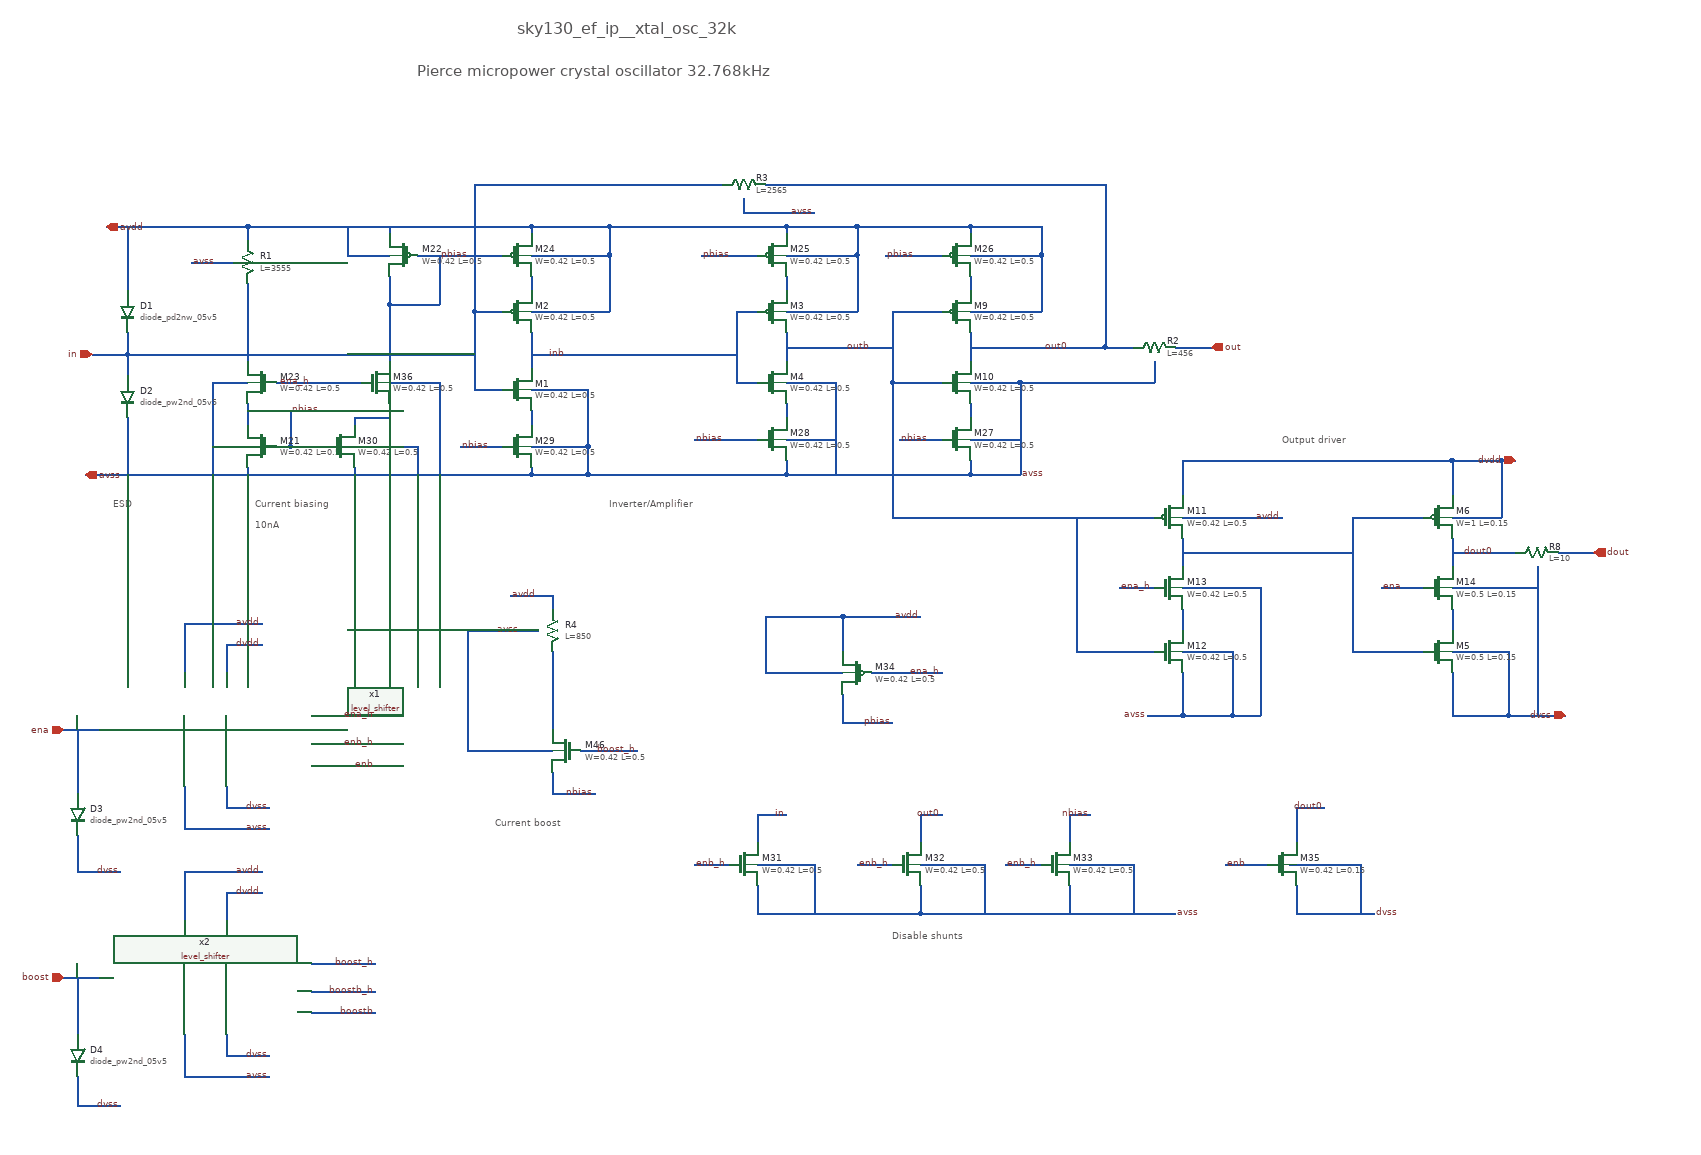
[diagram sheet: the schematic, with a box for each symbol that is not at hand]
v {xschem version=3.4.5 file_version=1.2
}
G {}
K {}
V {}
S {}
E {}
T {Inverter/Amplifier} 0 210 0 0 0.4 0.4 {}
T {Output driver} 950 120 0 0 0.4 0.4 {}
T {Disable shunts} 400 820 0 0 0.4 0.4 {}
T {Pierce micropower crystal oscillator 32.768kHz} -270 -400 0 0 0.65 0.65 {}
T {Current biasing} -500 210 0 0 0.4 0.4 {}
T {ESD} -700 210 0 0 0.4 0.4 {}
T {10nA} -500 240 0 0 0.4 0.4 {}
T {Current boost} -160 660 0 0 0.4 0.4 {}
T {sky130_ef_ip__xtal_osc_32k} -130 -460 0 0 0.7 0.7 {}
N -110 -20 -110 30 {
lab=inb}
N -190 -50 -150 -50 {
lab=in}
N -190 -50 -190 60 {
lab=in}
N -190 60 -150 60 {
lab=in}
N 250 -170 320 -170 {
lab=avdd}
N 250 180 310 180 {
lab=avss}
N -110 180 -30 180 {
lab=avss}
N -30 60 -30 140 {
lab=avss}
N -110 60 -30 60 {
lab=avss}
N -110 -50 0 -50 {
lab=avdd}
N 0 -130 0 -50 {
lab=avdd}
N -110 -170 0 -170 {
lab=avdd}
N 250 -20 250 20 {
lab=outb}
N 180 -50 180 50 {
lab=inb}
N 250 50 320 50 {
lab=avss}
N 310 180 340 180 {
lab=avss}
N 320 -170 350 -170 {
lab=avdd}
N 250 -50 350 -50 {
lab=avdd}
N 350 -130 350 -50 {
lab=avdd}
N 1190 160 1190 210 {
lab=dvdd}
N 1190 240 1260 240 {
lab=dvdd}
N 1260 160 1260 240 {
lab=dvdd}
N 1190 460 1190 520 {
lab=dvss}
N 1190 430 1270 430 {
lab=dvss}
N 1270 430 1270 520 {
lab=dvss}
N 220 -230 700 -230 {
lab=out0}
N 700 -230 700 -0 {
lab=out0}
N 720 0 740 -0 {
lab=out0}
N 800 -0 850 0 {
lab=out}
N 1190 160 1260 160 {
lab=dvdd}
N 1260 160 1280 160 {
lab=dvdd}
N 1190 520 1270 520 {
lab=dvss}
N 510 -170 580 -170 {
lab=avdd}
N 510 180 570 180 {
lab=avss}
N 510 -20 510 20 {
lab=out0}
N 420 -50 470 -50 {
lab=outb}
N 400 -50 400 50 {
lab=outb}
N 420 50 470 50 {
lab=outb}
N 510 50 580 50 {
lab=avss}
N 580 50 580 110 {
lab=avss}
N 580 110 580 140 {
lab=avss}
N 580 -170 610 -170 {
lab=avdd}
N 510 -50 610 -50 {
lab=avdd}
N 610 -130 610 -50 {
lab=avdd}
N 340 180 510 180 {
lab=avss}
N 570 180 580 180 {
lab=avss}
N 350 -170 510 -170 {
lab=avdd}
N 110 -170 250 -170 {
lab=avdd}
N 810 160 880 160 {
lab=dvdd}
N 810 160 810 210 {
lab=dvdd}
N 810 460 810 510 {
lab=avss}
N 810 510 810 520 {
lab=avss}
N 810 520 870 520 {
lab=avss}
N 720 430 770 430 {
lab=outb}
N 810 430 880 430 {
lab=avss}
N 880 430 880 490 {
lab=avss}
N 880 490 880 520 {
lab=avss}
N 880 160 910 160 {
lab=dvdd}
N 810 240 910 240 {
lab=avdd}
N 870 520 880 520 {
lab=avss}
N 910 160 1190 160 {
lab=dvdd}
N 910 240 950 240 {
lab=avdd}
N 400 50 400 240 {
lab=outb}
N 700 -0 720 0 {
lab=out0}
N 510 -0 700 0 {
lab=out0}
N 0 -170 0 -130 {
lab=avdd}
N 350 -170 350 -130 {
lab=avdd}
N 610 -170 610 -130 {
lab=avdd}
N -30 140 -30 180 {
lab=avss}
N 580 140 580 180 {
lab=avss}
N 320 50 320 180 {
lab=avss}
N 400 -50 420 -50 {
lab=outb}
N 400 50 420 50 {
lab=outb}
N 250 -0 400 -0 {
lab=outb}
N -680 -20 -680 10 {
lab=in}
N -680 10 -680 40 {
lab=in}
N -510 -170 -110 -170 {
lab=avdd}
N -680 -170 -680 -80 {
lab=avdd}
N -680 100 -680 180 {
lab=avss}
N 1270 520 1350 520 {
lab=dvss}
N 1190 290 1280 290 {
lab=dout0}
N 1340 290 1390 290 {
lab=dout}
N 1310 310 1310 520 {
lab=dvss}
N 810 340 920 340 {
lab=avss}
N 920 340 920 520 {
lab=avss}
N 1190 340 1310 340 {
lab=dvss}
N 810 270 810 310 {
lab=#net1}
N 810 370 810 400 {
lab=#net2}
N 1190 270 1190 310 {
lab=dout0}
N 1190 370 1190 400 {
lab=#net3}
N 660 240 660 430 {
lab=outb}
N 660 430 720 430 {
lab=outb}
N 810 290 1050 290 {
lab=#net1}
N 1050 240 1150 240 {
lab=#net1}
N 1050 240 1050 430 {
lab=#net1}
N 1050 430 1150 430 {
lab=#net1}
N 180 -50 210 -50 {
lab=inb}
N 180 50 210 50 {
lab=inb}
N 720 340 770 340 {
lab=ena_h}
N 190 -210 190 -190 {
lab=avss}
N 190 -190 290 -190 {
lab=avss}
N 770 20 770 50 {
lab=avss}
N 580 50 770 50 {
lab=avss}
N 0 -170 110 -170 {
lab=avdd}
N -190 -230 -190 -50 {
lab=in}
N -190 -230 160 -230 {
lab=in}
N 400 240 770 240 {
lab=outb}
N 510 80 510 100 {
lab=#net4}
N 510 130 580 130 {
lab=avss}
N 510 160 510 180 {
lab=avss}
N 510 -100 510 -80 {
lab=#net5}
N 510 -170 510 -160 {
lab=avdd}
N 510 -130 610 -130 {
lab=avdd}
N -110 -130 0 -130 {
lab=avdd}
N 250 -130 350 -130 {
lab=avdd}
N 250 -170 250 -160 {
lab=avdd}
N 250 -100 250 -80 {
lab=#net6}
N -110 -100 -110 -80 {
lab=#net7}
N -110 -170 -110 -160 {
lab=avdd}
N -110 90 -110 110 {
lab=#net8}
N -110 140 -30 140 {
lab=avss}
N -110 170 -110 180 {
lab=avss}
N 250 160 250 180 {
lab=avss}
N 250 80 250 100 {
lab=#net9}
N 250 130 320 130 {
lab=avss}
N -270 -130 -150 -130 {
lab=pbias}
N 130 -130 210 -130 {
lab=pbias}
N 390 -130 470 -130 {
lab=pbias}
N 410 130 470 130 {
lab=nbias}
N 120 130 210 130 {
lab=nbias}
N -110 10 180 10 {
lab=inb}
N -30 180 250 180 {
lab=avss}
N -510 170 -510 180 {
lab=avss}
N -730 10 -680 10 {
lab=in}
N -590 10 -190 10 {
lab=in}
N -470 140 -450 140 {
lab=nbias}
N -450 90 -450 140 {
lab=nbias}
N -510 90 -450 90 {
lab=nbias}
N -510 -170 -510 -150 {
lab=avdd}
N -510 80 -510 110 {
lab=nbias}
N -680 10 -590 10 {
lab=in}
N -590 -120 -530 -120 {
lab=avss}
N -510 -90 -510 20 {
lab=#net10}
N -450 140 -400 140 {
lab=nbias}
N -210 140 -150 140 {
lab=nbias}
N -360 170 -360 180 {
lab=avss}
N -360 140 -270 140 {
lab=avss}
N -270 140 -270 180 {
lab=avss}
N -310 -100 -310 -60 {
lab=pbias}
N -310 -60 -240 -60 {
lab=pbias}
N -240 -130 -240 -60 {
lab=pbias}
N -370 -130 -310 -130 {
lab=avdd}
N -370 -170 -370 -130 {
lab=avdd}
N -710 -170 -510 -170 {
lab=avdd}
N -740 180 -110 180 {
lab=avss}
N -560 50 -510 50 {
lab=avss}
N -560 50 -560 180 {
lab=avss}
N -560 140 -510 140 {
lab=avss}
N 210 760 210 800 {
lab=avss}
N 210 800 440 800 {
lab=avss}
N 440 760 440 800 {
lab=avss}
N 440 730 530 730 {
lab=avss}
N 530 730 530 800 {
lab=avss}
N 210 730 290 730 {
lab=avss}
N 290 730 290 800 {
lab=avss}
N 440 660 440 700 {
lab=out0}
N 440 660 470 660 {
lab=out0}
N 210 660 210 700 {
lab=in}
N 210 660 250 660 {
lab=in}
N 120 730 170 730 {
lab=enb_h}
N 350 730 400 730 {
lab=enb_h}
N 650 760 650 800 {
lab=avss}
N 650 730 740 730 {
lab=avss}
N 740 730 740 800 {
lab=avss}
N 650 660 650 700 {
lab=nbias}
N 650 660 680 660 {
lab=nbias}
N 560 730 610 730 {
lab=enb_h}
N 440 800 800 800 {
lab=avss}
N 330 380 330 430 {
lab=avdd}
N 330 380 440 380 {
lab=avdd}
N 220 460 330 460 {
lab=avdd}
N 220 380 220 460 {
lab=avdd}
N 220 380 330 380 {
lab=avdd}
N 370 460 470 460 {
lab=ena_h}
N 330 490 330 530 {
lab=pbias}
N 330 530 400 530 {
lab=pbias}
N 1090 340 1150 340 {
lab=ena}
N 870 730 930 730 {
lab=enb}
N 970 650 970 700 {
lab=dout0}
N 970 650 1010 650 {
lab=dout0}
N 970 760 970 800 {
lab=dvss}
N 970 800 1080 800 {
lab=dvss}
N 960 730 1060 730 {
lab=dvss}
N 1060 730 1060 800 {
lab=dvss}
N -360 100 -360 110 {
lab=#net11}
N -360 100 -310 100 {
lab=#net11}
N -310 90 -310 100 {
lab=#net11}
N -310 20 -310 30 {
lab=pbias}
N -310 80 -310 90 {
lab=#net11}
N -310 50 -240 50 {
lab=avss}
N -240 50 -240 180 {
lab=avss}
N -310 -60 -310 20 {
lab=pbias}
N -470 50 -350 50 {
lab=ena_h}
N -310 -170 -310 -160 {
lab=avdd}
N -80 630 -20 630 {
lab=nbias}
N -80 350 -80 370 {
lab=avdd}
N -80 430 -80 540 {
lab=#net12}
N -140 350 -80 350 {
lab=avdd}
N -200 570 -80 570 {
lab=avss}
N -200 400 -200 570 {
lab=avss}
N -200 400 -100 400 {
lab=avss}
N -80 600 -80 630 {
lab=nbias}
N -40 570 40 570 {
lab=boost_h}
N -770 540 -720 540 {
lab=ena}
N -770 890 -720 890 {
lab=boost}
N -420 520 -330 520 {
lab=ena_h}
N -420 560 -330 560 {
lab=enb_h}
N -420 870 -330 870 {
lab=boost_h}
N -420 910 -330 910 {
lab=boostb_h}
N -540 420 -540 460 {
lab=dvdd}
N -540 420 -490 420 {
lab=dvdd}
N -600 390 -600 460 {
lab=avdd}
N -600 390 -490 390 {
lab=avdd}
N -540 620 -540 650 {
lab=dvss}
N -540 650 -480 650 {
lab=dvss}
N -600 620 -600 680 {
lab=avss}
N -600 680 -480 680 {
lab=avss}
N -540 770 -540 810 {
lab=dvdd}
N -540 770 -490 770 {
lab=dvdd}
N -600 740 -600 810 {
lab=avdd}
N -600 740 -490 740 {
lab=avdd}
N -540 970 -540 1000 {
lab=dvss}
N -540 1000 -480 1000 {
lab=dvss}
N -600 970 -600 1030 {
lab=avss}
N -600 1030 -480 1030 {
lab=avss}
N -420 590 -330 590 {
lab=enb}
N -420 940 -330 940 {
lab=boostb}
N 880 520 920 520 {
lab=avss}
N 760 520 810 520 {
lab=avss}
N -750 1030 -750 1070 {
lab=dvss}
N -750 1070 -690 1070 {
lab=dvss}
N -750 690 -750 740 {
lab=dvss}
N -750 740 -690 740 {
lab=dvss}
N -750 540 -750 630 {
lab=ena}
N -750 890 -750 970 {
lab=boost}
C {sky130_fd_pr/nfet_g5v0d10v5.sym} -130 60 0 0 {name=M1
L=0.5
W=0.42
nf=1
mult=1
ad="'int((nf+1)/2) * W/nf * 0.29'" 
pd="'2*int((nf+1)/2) * (W/nf + 0.29)'"
as="'int((nf+2)/2) * W/nf * 0.29'" 
ps="'2*int((nf+2)/2) * (W/nf + 0.29)'"
nrd="'0.29 / W'" nrs="'0.29 / W'"
sa=0 sb=0 sd=0
model=nfet_g5v0d10v5
spiceprefix=X
}
C {sky130_fd_pr/pfet_g5v0d10v5.sym} -130 -50 0 0 {name=M2
L=0.5
W=0.42
nf=1
mult=1
ad="'int((nf+1)/2) * W/nf * 0.29'" 
pd="'2*int((nf+1)/2) * (W/nf + 0.29)'"
as="'int((nf+2)/2) * W/nf * 0.29'" 
ps="'2*int((nf+2)/2) * (W/nf + 0.29)'"
nrd="'0.29 / W'" nrs="'0.29 / W'"
sa=0 sb=0 sd=0
model=pfet_g5v0d10v5
spiceprefix=X
}
C {devices/ipin.sym} -730 10 0 0 {name=p1 lab=in}
C {devices/opin.sym} 850 0 0 0 {name=p2 lab=out}
C {devices/iopin.sym} -710 -170 0 1 {name=p3 lab=avdd}
C {devices/iopin.sym} -740 180 0 1 {name=p4 lab=avss}
C {devices/iopin.sym} 1350 520 0 0 {name=p6 lab=dvss}
C {devices/iopin.sym} 1280 160 0 0 {name=p7 lab=dvdd}
C {sky130_fd_pr/pfet_g5v0d10v5.sym} 230 -50 0 0 {name=M3
L=0.5
W=0.42
nf=1
mult=1
ad="'int((nf+1)/2) * W/nf * 0.29'" 
pd="'2*int((nf+1)/2) * (W/nf + 0.29)'"
as="'int((nf+2)/2) * W/nf * 0.29'" 
ps="'2*int((nf+2)/2) * (W/nf + 0.29)'"
nrd="'0.29 / W'" nrs="'0.29 / W'"
sa=0 sb=0 sd=0
model=pfet_g5v0d10v5
spiceprefix=X
}
C {sky130_fd_pr/nfet_g5v0d10v5.sym} 230 50 0 0 {name=M4
L=0.5
W=0.42
nf=1
mult=1
ad="'int((nf+1)/2) * W/nf * 0.29'" 
pd="'2*int((nf+1)/2) * (W/nf + 0.29)'"
as="'int((nf+2)/2) * W/nf * 0.29'" 
ps="'2*int((nf+2)/2) * (W/nf + 0.29)'"
nrd="'0.29 / W'" nrs="'0.29 / W'"
sa=0 sb=0 sd=0
model=nfet_g5v0d10v5
spiceprefix=X
}
C {sky130_fd_pr/nfet_01v8.sym} 1170 430 0 0 {name=M5
L=0.15
W=0.5
nf=1
mult=1
ad="'int((nf+1)/2) * W/nf * 0.29'" 
pd="'2*int((nf+1)/2) * (W/nf + 0.29)'"
as="'int((nf+2)/2) * W/nf * 0.29'" 
ps="'2*int((nf+2)/2) * (W/nf + 0.29)'"
nrd="'0.29 / W'" nrs="'0.29 / W'"
sa=0 sb=0 sd=0
model=nfet_01v8
spiceprefix=X
}
C {sky130_fd_pr/pfet_01v8.sym} 1170 240 0 0 {name=M6
L=0.15
W=1
nf=1
mult=1
ad="'int((nf+1)/2) * W/nf * 0.29'" 
pd="'2*int((nf+1)/2) * (W/nf + 0.29)'"
as="'int((nf+2)/2) * W/nf * 0.29'" 
ps="'2*int((nf+2)/2) * (W/nf + 0.29)'"
nrd="'0.29 / W'" nrs="'0.29 / W'"
sa=0 sb=0 sd=0
model=pfet_01v8
spiceprefix=X
}
C {devices/ipin.sym} -770 540 0 0 {name=p5 lab=ena}
C {sky130_fd_pr/res_high_po_0p69.sym} 770 0 3 0 {name=R2
L=456
model=res_high_po_0p69
spiceprefix=X
mult=1}
C {devices/lab_wire.sym} -60 10 0 0 {name=p11 sig_type=std_logic lab=inb}
C {devices/lab_wire.sym} 370 0 0 0 {name=p12 sig_type=std_logic lab=outb}
C {sky130_fd_pr/res_xhigh_po_0p35.sym} 190 -230 3 0 {name=R3
L=2565
model=res_xhigh_po_0p35
spiceprefix=X
mult=1}
C {devices/opin.sym} 1390 290 0 0 {name=p13 lab=dout}
C {sky130_fd_pr/pfet_g5v0d10v5.sym} 490 -50 0 0 {name=M9
L=0.5
W=0.42
nf=1
mult=1
ad="'int((nf+1)/2) * W/nf * 0.29'" 
pd="'2*int((nf+1)/2) * (W/nf + 0.29)'"
as="'int((nf+2)/2) * W/nf * 0.29'" 
ps="'2*int((nf+2)/2) * (W/nf + 0.29)'"
nrd="'0.29 / W'" nrs="'0.29 / W'"
sa=0 sb=0 sd=0
model=pfet_g5v0d10v5
spiceprefix=X
}
C {sky130_fd_pr/nfet_g5v0d10v5.sym} 490 50 0 0 {name=M10
L=0.5
W=0.42
nf=1
mult=1
ad="'int((nf+1)/2) * W/nf * 0.29'" 
pd="'2*int((nf+1)/2) * (W/nf + 0.29)'"
as="'int((nf+2)/2) * W/nf * 0.29'" 
ps="'2*int((nf+2)/2) * (W/nf + 0.29)'"
nrd="'0.29 / W'" nrs="'0.29 / W'"
sa=0 sb=0 sd=0
model=nfet_g5v0d10v5
spiceprefix=X
}
C {sky130_fd_pr/pfet_g5v0d10v5.sym} 790 240 0 0 {name=M11
L=0.5
W=0.42
nf=1
mult=1
ad="'int((nf+1)/2) * W/nf * 0.29'" 
pd="'2*int((nf+1)/2) * (W/nf + 0.29)'"
as="'int((nf+2)/2) * W/nf * 0.29'" 
ps="'2*int((nf+2)/2) * (W/nf + 0.29)'"
nrd="'0.29 / W'" nrs="'0.29 / W'"
sa=0 sb=0 sd=0
model=pfet_g5v0d10v5
spiceprefix=X
}
C {sky130_fd_pr/nfet_g5v0d10v5.sym} 790 430 0 0 {name=M12
L=0.5
W=0.42
nf=1
mult=1
ad="'int((nf+1)/2) * W/nf * 0.29'" 
pd="'2*int((nf+1)/2) * (W/nf + 0.29)'"
as="'int((nf+2)/2) * W/nf * 0.29'" 
ps="'2*int((nf+2)/2) * (W/nf + 0.29)'"
nrd="'0.29 / W'" nrs="'0.29 / W'"
sa=0 sb=0 sd=0
model=nfet_g5v0d10v5
spiceprefix=X
}
C {devices/lab_wire.sym} 950 240 0 0 {name=p14 sig_type=std_logic lab=avdd}
C {sky130_fd_pr/diode.sym} -680 -50 0 0 {name=D1
model=diode_pd2nw_05v5
area=2.025e11
pj=1.8e6
}
C {sky130_fd_pr/diode.sym} -680 70 0 0 {name=D2
model=diode_pw2nd_05v5
area=2.025e11
pj=1.8e6
}
C {sky130_fd_pr/res_high_po_0p69.sym} 1310 290 1 1 {name=R8
L=10
model=res_high_po_0p69
spiceprefix=X
mult=1}
C {sky130_fd_pr/nfet_g5v0d10v5.sym} 790 340 0 0 {name=M13
L=0.5
W=0.42
nf=1
mult=1
ad="'int((nf+1)/2) * W/nf * 0.29'" 
pd="'2*int((nf+1)/2) * (W/nf + 0.29)'"
as="'int((nf+2)/2) * W/nf * 0.29'" 
ps="'2*int((nf+2)/2) * (W/nf + 0.29)'"
nrd="'0.29 / W'" nrs="'0.29 / W'"
sa=0 sb=0 sd=0
model=nfet_g5v0d10v5
spiceprefix=X
}
C {sky130_fd_pr/nfet_01v8.sym} 1170 340 0 0 {name=M14
L=0.15
W=0.5
nf=1
mult=1
ad="'int((nf+1)/2) * W/nf * 0.29'" 
pd="'2*int((nf+1)/2) * (W/nf + 0.29)'"
as="'int((nf+2)/2) * W/nf * 0.29'" 
ps="'2*int((nf+2)/2) * (W/nf + 0.29)'"
nrd="'0.29 / W'" nrs="'0.29 / W'"
sa=0 sb=0 sd=0
model=nfet_01v8
spiceprefix=X
}
C {devices/lab_wire.sym} 1090 340 0 1 {name=p18 sig_type=std_logic lab=ena}
C {devices/lab_wire.sym} 290 -190 0 0 {name=p25 sig_type=std_logic lab=avss}
C {devices/lab_pin.sym} 580 180 0 1 {name=p30 sig_type=std_logic lab=avss}
C {sky130_fd_pr/pfet_g5v0d10v5.sym} -130 -130 0 0 {name=M24
L=0.5
W=0.42
nf=1
mult=1
ad="'int((nf+1)/2) * W/nf * 0.29'" 
pd="'2*int((nf+1)/2) * (W/nf + 0.29)'"
as="'int((nf+2)/2) * W/nf * 0.29'" 
ps="'2*int((nf+2)/2) * (W/nf + 0.29)'"
nrd="'0.29 / W'" nrs="'0.29 / W'"
sa=0 sb=0 sd=0
model=pfet_g5v0d10v5
spiceprefix=X
}
C {sky130_fd_pr/pfet_g5v0d10v5.sym} 230 -130 0 0 {name=M25
L=0.5
W=0.42
nf=1
mult=1
ad="'int((nf+1)/2) * W/nf * 0.29'" 
pd="'2*int((nf+1)/2) * (W/nf + 0.29)'"
as="'int((nf+2)/2) * W/nf * 0.29'" 
ps="'2*int((nf+2)/2) * (W/nf + 0.29)'"
nrd="'0.29 / W'" nrs="'0.29 / W'"
sa=0 sb=0 sd=0
model=pfet_g5v0d10v5
spiceprefix=X
}
C {sky130_fd_pr/pfet_g5v0d10v5.sym} 490 -130 0 0 {name=M26
L=0.5
W=0.42
nf=1
mult=1
ad="'int((nf+1)/2) * W/nf * 0.29'" 
pd="'2*int((nf+1)/2) * (W/nf + 0.29)'"
as="'int((nf+2)/2) * W/nf * 0.29'" 
ps="'2*int((nf+2)/2) * (W/nf + 0.29)'"
nrd="'0.29 / W'" nrs="'0.29 / W'"
sa=0 sb=0 sd=0
model=pfet_g5v0d10v5
spiceprefix=X
}
C {sky130_fd_pr/nfet_g5v0d10v5.sym} 490 130 0 0 {name=M27
L=0.5
W=0.42
nf=1
mult=1
ad="'int((nf+1)/2) * W/nf * 0.29'" 
pd="'2*int((nf+1)/2) * (W/nf + 0.29)'"
as="'int((nf+2)/2) * W/nf * 0.29'" 
ps="'2*int((nf+2)/2) * (W/nf + 0.29)'"
nrd="'0.29 / W'" nrs="'0.29 / W'"
sa=0 sb=0 sd=0
model=nfet_g5v0d10v5
spiceprefix=X
}
C {sky130_fd_pr/nfet_g5v0d10v5.sym} 230 130 0 0 {name=M28
L=0.5
W=0.42
nf=1
mult=1
ad="'int((nf+1)/2) * W/nf * 0.29'" 
pd="'2*int((nf+1)/2) * (W/nf + 0.29)'"
as="'int((nf+2)/2) * W/nf * 0.29'" 
ps="'2*int((nf+2)/2) * (W/nf + 0.29)'"
nrd="'0.29 / W'" nrs="'0.29 / W'"
sa=0 sb=0 sd=0
model=nfet_g5v0d10v5
spiceprefix=X
}
C {sky130_fd_pr/nfet_g5v0d10v5.sym} -130 140 0 0 {name=M29
L=0.5
W=0.42
nf=1
mult=1
ad="'int((nf+1)/2) * W/nf * 0.29'" 
pd="'2*int((nf+1)/2) * (W/nf + 0.29)'"
as="'int((nf+2)/2) * W/nf * 0.29'" 
ps="'2*int((nf+2)/2) * (W/nf + 0.29)'"
nrd="'0.29 / W'" nrs="'0.29 / W'"
sa=0 sb=0 sd=0
model=nfet_g5v0d10v5
spiceprefix=X
}
C {devices/lab_wire.sym} -210 140 0 1 {name=p15 sig_type=std_logic lab=nbias
}
C {devices/lab_wire.sym} -240 -130 0 1 {name=p16 sig_type=std_logic lab=pbias
}
C {devices/lab_wire.sym} 130 -130 0 1 {name=p17 sig_type=std_logic lab=pbias
}
C {devices/lab_wire.sym} 390 -130 0 1 {name=p31 sig_type=std_logic lab=pbias
}
C {devices/lab_wire.sym} 120 130 0 1 {name=p32 sig_type=std_logic lab=nbias
}
C {devices/lab_wire.sym} 410 130 0 1 {name=p33 sig_type=std_logic lab=nbias
}
C {sky130_fd_pr/nfet_g5v0d10v5.sym} -490 140 0 1 {name=M21
L=0.5
W=0.42
nf=1
mult=1
ad="'int((nf+1)/2) * W/nf * 0.29'" 
pd="'2*int((nf+1)/2) * (W/nf + 0.29)'"
as="'int((nf+2)/2) * W/nf * 0.29'" 
ps="'2*int((nf+2)/2) * (W/nf + 0.29)'"
nrd="'0.29 / W'" nrs="'0.29 / W'"
sa=0 sb=0 sd=0
model=nfet_g5v0d10v5
spiceprefix=X
}
C {sky130_fd_pr/pfet_g5v0d10v5.sym} -290 -130 0 1 {name=M22
L=0.5
W=0.42
nf=1
mult=1
ad="'int((nf+1)/2) * W/nf * 0.29'" 
pd="'2*int((nf+1)/2) * (W/nf + 0.29)'"
as="'int((nf+2)/2) * W/nf * 0.29'" 
ps="'2*int((nf+2)/2) * (W/nf + 0.29)'"
nrd="'0.29 / W'" nrs="'0.29 / W'"
sa=0 sb=0 sd=0
model=pfet_g5v0d10v5
spiceprefix=X
}
C {sky130_fd_pr/res_xhigh_po_0p35.sym} -510 -120 0 0 {name=R1
L=3555
model=res_xhigh_po_0p35
spiceprefix=X
mult=1}
C {devices/lab_wire.sym} -590 -120 0 1 {name=p26 sig_type=std_logic lab=avss}
C {sky130_fd_pr/nfet_g5v0d10v5.sym} -490 50 0 1 {name=M23
L=0.5
W=0.42
nf=1
mult=1
ad="'int((nf+1)/2) * W/nf * 0.29'" 
pd="'2*int((nf+1)/2) * (W/nf + 0.29)'"
as="'int((nf+2)/2) * W/nf * 0.29'" 
ps="'2*int((nf+2)/2) * (W/nf + 0.29)'"
nrd="'0.29 / W'" nrs="'0.29 / W'"
sa=0 sb=0 sd=0
model=nfet_g5v0d10v5
spiceprefix=X
}
C {devices/lab_wire.sym} -420 50 0 0 {name=p27 sig_type=std_logic lab=ena_h}
C {sky130_fd_pr/nfet_g5v0d10v5.sym} -380 140 0 0 {name=M30
L=0.5
W=0.42
nf=1
mult=1
ad="'int((nf+1)/2) * W/nf * 0.29'" 
pd="'2*int((nf+1)/2) * (W/nf + 0.29)'"
as="'int((nf+2)/2) * W/nf * 0.29'" 
ps="'2*int((nf+2)/2) * (W/nf + 0.29)'"
nrd="'0.29 / W'" nrs="'0.29 / W'"
sa=0 sb=0 sd=0
model=nfet_g5v0d10v5
spiceprefix=X
}
C {devices/lab_wire.sym} -450 90 0 1 {name=p28 sig_type=std_logic lab=nbias
}
C {sky130_fd_pr/nfet_g5v0d10v5.sym} 190 730 0 0 {name=M31
L=0.5
W=0.42
nf=1
mult=1
ad="'int((nf+1)/2) * W/nf * 0.29'" 
pd="'2*int((nf+1)/2) * (W/nf + 0.29)'"
as="'int((nf+2)/2) * W/nf * 0.29'" 
ps="'2*int((nf+2)/2) * (W/nf + 0.29)'"
nrd="'0.29 / W'" nrs="'0.29 / W'"
sa=0 sb=0 sd=0
model=nfet_g5v0d10v5
spiceprefix=X
}
C {sky130_fd_pr/nfet_g5v0d10v5.sym} 420 730 0 0 {name=M32
L=0.5
W=0.42
nf=1
mult=1
ad="'int((nf+1)/2) * W/nf * 0.29'" 
pd="'2*int((nf+1)/2) * (W/nf + 0.29)'"
as="'int((nf+2)/2) * W/nf * 0.29'" 
ps="'2*int((nf+2)/2) * (W/nf + 0.29)'"
nrd="'0.29 / W'" nrs="'0.29 / W'"
sa=0 sb=0 sd=0
model=nfet_g5v0d10v5
spiceprefix=X
}
C {devices/lab_pin.sym} 800 800 0 1 {name=p29 sig_type=std_logic lab=avss}
C {devices/lab_wire.sym} 120 730 0 1 {name=p34 sig_type=std_logic lab=enb_h}
C {devices/lab_wire.sym} 350 730 0 1 {name=p35 sig_type=std_logic lab=enb_h}
C {devices/lab_wire.sym} 250 660 0 0 {name=p36 sig_type=std_logic lab=in}
C {devices/lab_wire.sym} 470 660 0 0 {name=p37 sig_type=std_logic lab=out0}
C {sky130_fd_pr/nfet_g5v0d10v5.sym} 630 730 0 0 {name=M33
L=0.5
W=0.42
nf=1
mult=1
ad="'int((nf+1)/2) * W/nf * 0.29'" 
pd="'2*int((nf+1)/2) * (W/nf + 0.29)'"
as="'int((nf+2)/2) * W/nf * 0.29'" 
ps="'2*int((nf+2)/2) * (W/nf + 0.29)'"
nrd="'0.29 / W'" nrs="'0.29 / W'"
sa=0 sb=0 sd=0
model=nfet_g5v0d10v5
spiceprefix=X
}
C {devices/lab_wire.sym} 560 730 0 1 {name=p38 sig_type=std_logic lab=enb_h}
C {devices/lab_wire.sym} 680 660 0 0 {name=p39 sig_type=std_logic lab=nbias}
C {sky130_fd_pr/pfet_g5v0d10v5.sym} 350 460 0 1 {name=M34
L=0.5
W=0.42
nf=1
mult=1
ad="'int((nf+1)/2) * W/nf * 0.29'" 
pd="'2*int((nf+1)/2) * (W/nf + 0.29)'"
as="'int((nf+2)/2) * W/nf * 0.29'" 
ps="'2*int((nf+2)/2) * (W/nf + 0.29)'"
nrd="'0.29 / W'" nrs="'0.29 / W'"
sa=0 sb=0 sd=0
model=pfet_g5v0d10v5
spiceprefix=X
}
C {devices/lab_wire.sym} 440 380 0 0 {name=p40 sig_type=std_logic lab=avdd}
C {devices/lab_wire.sym} 470 460 0 0 {name=p41 sig_type=std_logic lab=ena_h}
C {devices/lab_wire.sym} 400 530 0 0 {name=p42 sig_type=std_logic lab=pbias
}
C {devices/lab_wire.sym} 720 340 0 1 {name=p43 sig_type=std_logic lab=ena_h}
C {sky130_fd_pr/nfet_01v8.sym} 950 730 0 0 {name=M35
L=0.15
W=0.42
nf=1
mult=1
ad="'int((nf+1)/2) * W/nf * 0.29'" 
pd="'2*int((nf+1)/2) * (W/nf + 0.29)'"
as="'int((nf+2)/2) * W/nf * 0.29'" 
ps="'2*int((nf+2)/2) * (W/nf + 0.29)'"
nrd="'0.29 / W'" nrs="'0.29 / W'"
sa=0 sb=0 sd=0
model=nfet_01v8
spiceprefix=X
}
C {devices/lab_wire.sym} 870 730 0 1 {name=p44 sig_type=std_logic lab=enb}
C {devices/lab_wire.sym} 1010 650 0 0 {name=p45 sig_type=std_logic lab=dout0}
C {devices/lab_pin.sym} 1080 800 2 0 {name=p46 sig_type=std_logic lab=dvss}
C {sky130_fd_pr/nfet_g5v0d10v5.sym} -330 50 0 0 {name=M36
L=0.5
W=0.42
nf=1
mult=1
ad="'int((nf+1)/2) * W/nf * 0.29'" 
pd="'2*int((nf+1)/2) * (W/nf + 0.29)'"
as="'int((nf+2)/2) * W/nf * 0.29'" 
ps="'2*int((nf+2)/2) * (W/nf + 0.29)'"
nrd="'0.29 / W'" nrs="'0.29 / W'"
sa=0 sb=0 sd=0
model=nfet_g5v0d10v5
spiceprefix=X
}
C {devices/ipin.sym} -770 890 0 0 {name=p49 lab=boost}
C {sky130_fd_pr/res_xhigh_po_0p35.sym} -80 400 0 0 {name=R4
L=850
model=res_xhigh_po_0p35
spiceprefix=X
mult=1}
C {devices/lab_wire.sym} -160 400 0 1 {name=p57 sig_type=std_logic lab=avss}
C {sky130_fd_pr/nfet_g5v0d10v5.sym} -60 570 0 1 {name=M46
L=0.5
W=0.42
nf=1
mult=1
ad="'int((nf+1)/2) * W/nf * 0.29'" 
pd="'2*int((nf+1)/2) * (W/nf + 0.29)'"
as="'int((nf+2)/2) * W/nf * 0.29'" 
ps="'2*int((nf+2)/2) * (W/nf + 0.29)'"
nrd="'0.29 / W'" nrs="'0.29 / W'"
sa=0 sb=0 sd=0
model=nfet_g5v0d10v5
spiceprefix=X
}
C {devices/lab_wire.sym} -20 630 0 0 {name=p58 sig_type=std_logic lab=nbias
}
C {devices/lab_wire.sym} -140 350 0 1 {name=p59 sig_type=std_logic lab=avdd}
C {devices/lab_wire.sym} 40 570 0 0 {name=p60 sig_type=std_logic lab=boost_h}
C {level_shifter.sym} -570 540 0 0 {name=x1}
C {level_shifter.sym} -570 890 0 0 {name=x2}
C {devices/lab_wire.sym} -330 870 0 0 {name=p61 sig_type=std_logic lab=boost_h}
C {devices/lab_wire.sym} -330 910 0 0 {name=p62 sig_type=std_logic lab=boostb_h}
C {devices/lab_wire.sym} -330 520 0 0 {name=p63 sig_type=std_logic lab=ena_h}
C {devices/lab_wire.sym} -330 560 0 0 {name=p64 sig_type=std_logic lab=enb_h}
C {devices/lab_wire.sym} -480 680 0 0 {name=p65 sig_type=std_logic lab=avss}
C {devices/lab_wire.sym} -480 650 0 0 {name=p66 sig_type=std_logic lab=dvss}
C {devices/lab_wire.sym} -490 420 0 0 {name=p67 sig_type=std_logic lab=dvdd}
C {devices/lab_wire.sym} -490 390 0 0 {name=p68 sig_type=std_logic lab=avdd}
C {devices/lab_wire.sym} -490 770 0 0 {name=p8 sig_type=std_logic lab=dvdd}
C {devices/lab_wire.sym} -490 740 0 0 {name=p9 sig_type=std_logic lab=avdd}
C {devices/lab_wire.sym} -480 1030 0 0 {name=p10 sig_type=std_logic lab=avss}
C {devices/lab_wire.sym} -480 1000 0 0 {name=p19 sig_type=std_logic lab=dvss}
C {devices/lab_wire.sym} -330 590 0 0 {name=p20 sig_type=std_logic lab=enb}
C {devices/lab_wire.sym} -330 940 0 0 {name=p21 sig_type=std_logic lab=boostb}
C {devices/lab_pin.sym} 760 520 0 0 {name=p22 sig_type=std_logic lab=avss}
C {devices/lab_wire.sym} 1250 290 0 0 {name=p23 sig_type=std_logic lab=dout0}
C {devices/lab_wire.sym} 650 0 0 0 {name=p24 sig_type=std_logic lab=out0}
C {sky130_fd_pr/diode.sym} -750 660 0 0 {name=D3
model=diode_pw2nd_05v5
area=2.025e11
pj=1.8e6
}
C {sky130_fd_pr/diode.sym} -750 1000 0 0 {name=D4
model=diode_pw2nd_05v5
area=2.025e11
pj=1.8e6
}
C {devices/lab_wire.sym} -690 1070 0 0 {name=p47 sig_type=std_logic lab=dvss}
C {devices/lab_wire.sym} -690 740 0 0 {name=p48 sig_type=std_logic lab=dvss}
